VERSION 5.7 ;
  NOWIREEXTENSIONATPIN ON ;
  DIVIDERCHAR "/" ;
  BUSBITCHARS "[]" ;
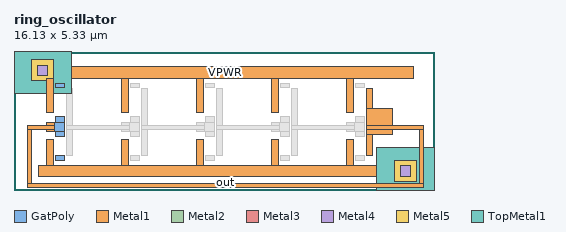
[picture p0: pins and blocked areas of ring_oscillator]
MACRO ring_oscillator
  CLASS BLOCK ;
  FOREIGN ring_oscillator ;
  ORIGIN 0.930 0.730 ;
  SIZE 16.130 BY 5.330 ;
  PIN out
    ANTENNAGATEAREA 0.641700 ;
    ANTENNADIFFAREA 0.632400 ;
    PORT
      LAYER GatPoly ;
        RECT 0.650 3.195 0.995 3.375 ;
        RECT 0.650 1.850 0.995 2.075 ;
        RECT 0.310 1.520 0.995 1.850 ;
        RECT 0.650 1.330 0.995 1.520 ;
        RECT 0.650 0.410 0.995 0.590 ;
      LAYER Metal1 ;
        RECT 12.590 2.400 12.820 3.175 ;
        RECT 0.310 1.765 0.625 1.850 ;
        RECT -0.400 1.605 0.625 1.765 ;
        RECT -0.400 -0.480 -0.240 1.605 ;
        RECT 0.310 1.520 0.625 1.605 ;
        RECT 12.590 1.765 13.590 2.400 ;
        RECT 12.590 1.605 14.800 1.765 ;
        RECT 12.590 1.400 13.590 1.605 ;
        RECT 12.590 0.610 12.820 1.400 ;
        RECT 14.640 -0.480 14.800 1.605 ;
        RECT -0.400 -0.640 14.800 -0.480 ;
    END
  END out
  PIN VPWR
    ANTENNADIFFAREA 6.224000 ;
    PORT
      LAYER Metal1 ;
        RECT 0.000 3.560 14.400 4.000 ;
        RECT 0.330 2.235 0.590 3.560 ;
        RECT 3.210 2.235 3.470 3.560 ;
        RECT 6.090 2.235 6.350 3.560 ;
        RECT 8.970 2.235 9.230 3.560 ;
        RECT 11.850 2.235 12.110 3.560 ;
      LAYER Metal2 ;
        RECT -0.030 3.670 0.370 4.070 ;
      LAYER Metal3 ;
        RECT -0.030 3.670 0.370 4.070 ;
      LAYER Metal4 ;
        RECT -0.030 3.670 0.370 4.070 ;
      LAYER Metal5 ;
        RECT -0.240 3.460 0.580 4.280 ;
      LAYER TopMetal1 ;
        RECT -0.930 2.960 1.270 4.600 ;
    END
  END VPWR
  PIN VGND
    ANTENNADIFFAREA 5.578000 ;
    PORT
      LAYER Metal1 ;
        RECT 0.330 0.220 0.590 1.210 ;
        RECT 3.210 0.220 3.470 1.210 ;
        RECT 6.090 0.220 6.350 1.210 ;
        RECT 8.970 0.220 9.230 1.210 ;
        RECT 11.850 0.220 12.110 1.210 ;
        RECT 0.000 -0.220 14.400 0.220 ;
      LAYER Metal2 ;
        RECT 13.900 -0.200 14.300 0.200 ;
      LAYER Metal3 ;
        RECT 13.900 -0.200 14.300 0.200 ;
      LAYER Metal4 ;
        RECT 13.900 -0.200 14.300 0.200 ;
      LAYER Metal5 ;
        RECT 13.690 -0.410 14.510 0.410 ;
      LAYER TopMetal1 ;
        RECT 13.000 -0.730 15.200 0.910 ;
    END
  END VGND
  OBS
      LAYER GatPoly ;
        RECT 3.530 3.195 3.875 3.375 ;
        RECT 6.410 3.195 6.755 3.375 ;
        RECT 9.290 3.195 9.635 3.375 ;
        RECT 12.170 3.195 12.515 3.375 ;
        RECT 3.530 1.850 3.875 2.075 ;
        RECT 6.410 1.850 6.755 2.075 ;
        RECT 9.290 1.850 9.635 2.075 ;
        RECT 12.170 1.850 12.515 2.075 ;
        RECT 3.190 1.520 3.875 1.850 ;
        RECT 6.070 1.520 6.755 1.850 ;
        RECT 8.950 1.520 9.635 1.850 ;
        RECT 11.830 1.520 12.515 1.850 ;
        RECT 3.530 1.330 3.875 1.520 ;
        RECT 6.410 1.330 6.755 1.520 ;
        RECT 9.290 1.330 9.635 1.520 ;
        RECT 12.170 1.330 12.515 1.520 ;
        RECT 3.530 0.410 3.875 0.590 ;
        RECT 6.410 0.410 6.755 0.590 ;
        RECT 9.290 0.410 9.635 0.590 ;
        RECT 12.170 0.410 12.515 0.590 ;
      LAYER Metal1 ;
        RECT 1.070 1.765 1.300 3.175 ;
        RECT 3.190 1.765 3.505 1.850 ;
        RECT 1.070 1.605 3.505 1.765 ;
        RECT 1.070 0.610 1.300 1.605 ;
        RECT 3.190 1.520 3.505 1.605 ;
        RECT 3.950 1.765 4.180 3.175 ;
        RECT 6.070 1.765 6.385 1.850 ;
        RECT 3.950 1.605 6.385 1.765 ;
        RECT 3.950 0.610 4.180 1.605 ;
        RECT 6.070 1.520 6.385 1.605 ;
        RECT 6.830 1.765 7.060 3.175 ;
        RECT 8.950 1.765 9.265 1.850 ;
        RECT 6.830 1.605 9.265 1.765 ;
        RECT 6.830 0.610 7.060 1.605 ;
        RECT 8.950 1.520 9.265 1.605 ;
        RECT 9.710 1.765 9.940 3.175 ;
        RECT 11.830 1.765 12.145 1.850 ;
        RECT 9.710 1.605 12.145 1.765 ;
        RECT 9.710 0.610 9.940 1.605 ;
        RECT 11.830 1.520 12.145 1.605 ;
  END
END ring_oscillator
END LIBRARY

